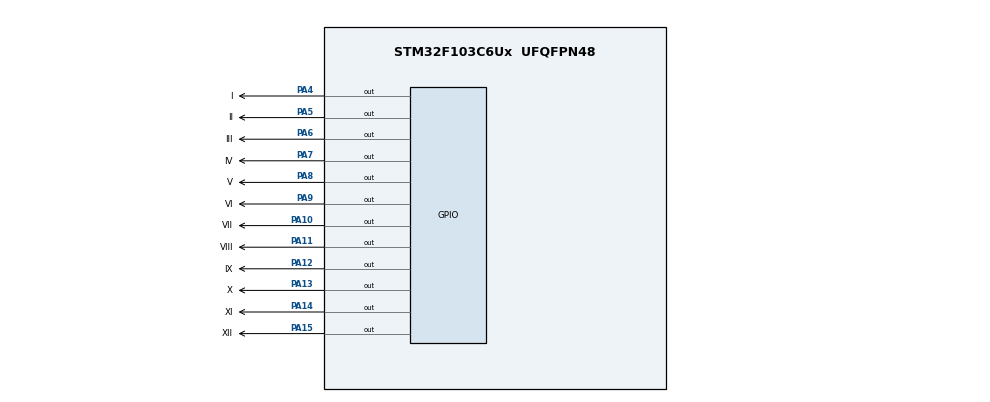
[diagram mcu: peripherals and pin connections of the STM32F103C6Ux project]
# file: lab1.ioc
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Mcu.Family=STM32F1
Mcu.Name=STM32F103C6Ux
Mcu.Package=UFQFPN48
NVIC.PriorityGroup=NVIC_PRIORITYGROUP_4
PA10.GPIO_Label=VII
PA10.Signal=GPIO_Output
PA11.GPIO_Label=VIII
PA11.Signal=GPIO_Output
PA12.GPIO_Label=IX
PA12.Signal=GPIO_Output
PA13.GPIO_Label=X
PA13.Signal=GPIO_Output
PA14.GPIO_Label=XI
PA14.Signal=GPIO_Output
PA15.GPIO_Label=XII
PA15.Signal=GPIO_Output
PA4.GPIO_Label=I
PA4.Signal=GPIO_Output
PA5.GPIO_Label=II
PA5.Signal=GPIO_Output
PA6.GPIO_Label=III
PA6.Signal=GPIO_Output
PA7.GPIO_Label=IV
PA7.Signal=GPIO_Output
PA8.GPIO_Label=V
PA8.Signal=GPIO_Output
PA9.GPIO_Label=VI
PA9.Signal=GPIO_Output
ProjectManager.HeapSize=0x200
ProjectManager.StackSize=0x400
ProjectManager.TargetToolchain=STM32CubeIDE
RCC.APB1Freq_Value=8000000
RCC.APB2Freq_Value=8000000
VP_SYS_VS_ND.Mode=No_Debug
board=custom

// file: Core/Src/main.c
/* USER CODE BEGIN Header */
/**
  ******************************************************************************
  * @file           : main.c
  * @brief          : Main program body
  ******************************************************************************
  * @attention
  *
  * <h2><center>&copy; Copyright (c) 2025 STMicroelectronics.
  * All rights reserved.</center></h2>
  *
  * This software component is licensed by ST under BSD 3-Clause license,
  * the "License"; You may not use this file except in compliance with the
  * License. You may obtain a copy of the License at:
  *                        opensource.org/licenses/BSD-3-Clause
  *
  ******************************************************************************
  */
/* USER CODE END Header */
#include "main.h"

void SystemClock_Config(void);
static void MX_GPIO_Init(void);

void display7SEG1(int num)
{
	if(num==0)
	{
		HAL_GPIO_WritePin(a1_GPIO_Port, a1_Pin, GPIO_PIN_RESET);
		HAL_GPIO_WritePin(b1_GPIO_Port, b1_Pin, GPIO_PIN_RESET);
		HAL_GPIO_WritePin(c1_GPIO_Port, c1_Pin, GPIO_PIN_RESET);
		HAL_GPIO_WritePin(d1_GPIO_Port, d1_Pin, GPIO_PIN_RESET);
		HAL_GPIO_WritePin(e1_GPIO_Port, e1_Pin, GPIO_PIN_RESET);
		HAL_GPIO_WritePin(f1_GPIO_Port, f1_Pin, GPIO_PIN_RESET);
		HAL_GPIO_WritePin(g1_GPIO_Port, g1_Pin, GPIO_PIN_SET);
		return;
	}

	if(num==100)
	{
		HAL_GPIO_WritePin(a1_GPIO_Port, a1_Pin, GPIO_PIN_SET);
		HAL_GPIO_WritePin(b1_GPIO_Port, b1_Pin, GPIO_PIN_RESET);
		HAL_GPIO_WritePin(c1_GPIO_Port, c1_Pin, GPIO_PIN_RESET);
		HAL_GPIO_WritePin(d1_GPIO_Port, d1_Pin, GPIO_PIN_SET);
		HAL_GPIO_WritePin(e1_GPIO_Port, e1_Pin, GPIO_PIN_SET);
		HAL_GPIO_WritePin(f1_GPIO_Port, f1_Pin, GPIO_PIN_SET);
		HAL_GPIO_WritePin(g1_GPIO_Port, g1_Pin, GPIO_PIN_SET);
		return;
	}

	if(num==200)
	{
		HAL_GPIO_WritePin(a1_GPIO_Port, a1_Pin, GPIO_PIN_RESET);
		HAL_GPIO_WritePin(b1_GPIO_Port, b1_Pin, GPIO_PIN_RESET);
		HAL_GPIO_WritePin(c1_GPIO_Port, c1_Pin, GPIO_PIN_SET);
		HAL_GPIO_WritePin(d1_GPIO_Port, d1_Pin, GPIO_PIN_RESET);
		HAL_GPIO_WritePin(e1_GPIO_Port, e1_Pin, GPIO_PIN_RESET);
		HAL_GPIO_WritePin(f1_GPIO_Port, f1_Pin, GPIO_PIN_SET);
		HAL_GPIO_WritePin(g1_GPIO_Port, g1_Pin, GPIO_PIN_RESET);
		return;
	}

	if(num==300)
	{
		HAL_GPIO_WritePin(a1_GPIO_Port, a1_Pin, GPIO_PIN_RESET);
		HAL_GPIO_WritePin(b1_GPIO_Port, b1_Pin, GPIO_PIN_RESET);
		HAL_GPIO_WritePin(c1_GPIO_Port, c1_Pin, GPIO_PIN_RESET);
		HAL_GPIO_WritePin(d1_GPIO_Port, d1_Pin, GPIO_PIN_RESET);
		HAL_GPIO_WritePin(e1_GPIO_Port, e1_Pin, GPIO_PIN_SET);
		HAL_GPIO_WritePin(f1_GPIO_Port, f1_Pin, GPIO_PIN_SET);
		HAL_GPIO_WritePin(g1_GPIO_Port, g1_Pin, GPIO_PIN_RESET);
		return;
	}

	if(num==400)
	{
		HAL_GPIO_WritePin(a1_GPIO_Port, a1_Pin, GPIO_PIN_SET);
		HAL_GPIO_WritePin(b1_GPIO_Port, b1_Pin, GPIO_PIN_RESET);
		HAL_GPIO_WritePin(c1_GPIO_Port, c1_Pin, GPIO_PIN_RESET);
		HAL_GPIO_WritePin(d1_GPIO_Port, d1_Pin, GPIO_PIN_SET);
		HAL_GPIO_WritePin(e1_GPIO_Port, e1_Pin, GPIO_PIN_SET);
		HAL_GPIO_WritePin(f1_GPIO_Port, f1_Pin, GPIO_PIN_RESET);
		HAL_GPIO_WritePin(g1_GPIO_Port, g1_Pin, GPIO_PIN_RESET);
		return;
	}

	if(num==500)
	{
		HAL_GPIO_WritePin(a1_GPIO_Port, a1_Pin, GPIO_PIN_RESET);
		HAL_GPIO_WritePin(b1_GPIO_Port, b1_Pin, GPIO_PIN_SET);
		HAL_GPIO_WritePin(c1_GPIO_Port, c1_Pin, GPIO_PIN_RESET);
		HAL_GPIO_WritePin(d1_GPIO_Port, d1_Pin, GPIO_PIN_RESET);
		HAL_GPIO_WritePin(e1_GPIO_Port, e1_Pin, GPIO_PIN_SET);
		HAL_GPIO_WritePin(f1_GPIO_Port, f1_Pin, GPIO_PIN_RESET);
		HAL_GPIO_WritePin(g1_GPIO_Port, g1_Pin, GPIO_PIN_RESET);
		return;
	}
}

void display7SEG2(int num)
{
	if(num==0)
	{
		HAL_GPIO_WritePin(a2_GPIO_Port, a2_Pin, GPIO_PIN_RESET);
		HAL_GPIO_WritePin(b2_GPIO_Port, b2_Pin, GPIO_PIN_RESET);
		HAL_GPIO_WritePin(c2_GPIO_Port, c2_Pin, GPIO_PIN_RESET);
		HAL_GPIO_WritePin(d2_GPIO_Port, d2_Pin, GPIO_PIN_RESET);
		HAL_GPIO_WritePin(e2_GPIO_Port, e2_Pin, GPIO_PIN_RESET);
		HAL_GPIO_WritePin(f2_GPIO_Port, f2_Pin, GPIO_PIN_RESET);
		HAL_GPIO_WritePin(g2_GPIO_Port, g2_Pin, GPIO_PIN_SET);
		return;
	}

	if(num==100)
	{
		HAL_GPIO_WritePin(a2_GPIO_Port, a2_Pin, GPIO_PIN_SET);
		HAL_GPIO_WritePin(b2_GPIO_Port, b2_Pin, GPIO_PIN_RESET);
		HAL_GPIO_WritePin(c2_GPIO_Port, c2_Pin, GPIO_PIN_RESET);
		HAL_GPIO_WritePin(d2_GPIO_Port, d2_Pin, GPIO_PIN_SET);
		HAL_GPIO_WritePin(e2_GPIO_Port, e2_Pin, GPIO_PIN_SET);
		HAL_GPIO_WritePin(f2_GPIO_Port, f2_Pin, GPIO_PIN_SET);
		HAL_GPIO_WritePin(g2_GPIO_Port, g2_Pin, GPIO_PIN_SET);
		return;
	}

	if(num==200)
	{
		HAL_GPIO_WritePin(a2_GPIO_Port, a2_Pin, GPIO_PIN_RESET);
		HAL_GPIO_WritePin(b2_GPIO_Port, b2_Pin, GPIO_PIN_RESET);
		HAL_GPIO_WritePin(c2_GPIO_Port, c2_Pin, GPIO_PIN_SET);
		HAL_GPIO_WritePin(d2_GPIO_Port, d2_Pin, GPIO_PIN_RESET);
		HAL_GPIO_WritePin(e2_GPIO_Port, e2_Pin, GPIO_PIN_RESET);
		HAL_GPIO_WritePin(f2_GPIO_Port, f2_Pin, GPIO_PIN_SET);
		HAL_GPIO_WritePin(g2_GPIO_Port, g2_Pin, GPIO_PIN_RESET);
		return;
	}

	if(num==300)
	{
		HAL_GPIO_WritePin(a2_GPIO_Port, a2_Pin, GPIO_PIN_RESET);
		HAL_GPIO_WritePin(b2_GPIO_Port, b2_Pin, GPIO_PIN_RESET);
		HAL_GPIO_WritePin(c2_GPIO_Port, c2_Pin, GPIO_PIN_RESET);
		HAL_GPIO_WritePin(d2_GPIO_Port, d2_Pin, GPIO_PIN_RESET);
		HAL_GPIO_WritePin(e2_GPIO_Port, e2_Pin, GPIO_PIN_SET);
		HAL_GPIO_WritePin(f2_GPIO_Port, f2_Pin, GPIO_PIN_SET);
		HAL_GPIO_WritePin(g2_GPIO_Port, g2_Pin, GPIO_PIN_RESET);
		return;
	}

	if(num==400)
	{
		HAL_GPIO_WritePin(a2_GPIO_Port, a2_Pin, GPIO_PIN_SET);
		HAL_GPIO_WritePin(b2_GPIO_Port, b2_Pin, GPIO_PIN_RESET);
		HAL_GPIO_WritePin(c2_GPIO_Port, c2_Pin, GPIO_PIN_RESET);
		HAL_GPIO_WritePin(d2_GPIO_Port, d2_Pin, GPIO_PIN_SET);
		HAL_GPIO_WritePin(e2_GPIO_Port, e2_Pin, GPIO_PIN_SET);
		HAL_GPIO_WritePin(f2_GPIO_Port, f2_Pin, GPIO_PIN_RESET);
		HAL_GPIO_WritePin(g2_GPIO_Port, g2_Pin, GPIO_PIN_RESET);
		return;
	}

	if(num==500)
	{
		HAL_GPIO_WritePin(a2_GPIO_Port, a2_Pin, GPIO_PIN_RESET);
		HAL_GPIO_WritePin(b2_GPIO_Port, b2_Pin, GPIO_PIN_SET);
		HAL_GPIO_WritePin(c2_GPIO_Port, c2_Pin, GPIO_PIN_RESET);
		HAL_GPIO_WritePin(d2_GPIO_Port, d2_Pin, GPIO_PIN_RESET);
		HAL_GPIO_WritePin(e2_GPIO_Port, e2_Pin, GPIO_PIN_SET);
		HAL_GPIO_WritePin(f2_GPIO_Port, f2_Pin, GPIO_PIN_RESET);
		HAL_GPIO_WritePin(g2_GPIO_Port, g2_Pin, GPIO_PIN_RESET);
		return;
	}
}

int main(void)
{

  /* MCU Configuration--------------------------------------------------------*/

  /* Reset of all peripherals, Initializes the Flash interface and the Systick. */
  HAL_Init();

  /* Configure the system clock */
  SystemClock_Config();

  /* Initialize all configured peripherals */
  MX_GPIO_Init();

  /* Infinite loop */
  /* USER CODE BEGIN WHILE */
	int count1=1000;
  int count2=1000;
  int counter1=400;
  int counter2=200;
  HAL_GPIO_WritePin(RED1_GPIO_Port, RED1_Pin, GPIO_PIN_RESET);
  HAL_GPIO_WritePin(YELLOW1_GPIO_Port, YELLOW1_Pin, GPIO_PIN_SET);
  HAL_GPIO_WritePin(GREEN1_GPIO_Port, GREEN1_Pin, GPIO_PIN_SET);
  HAL_GPIO_WritePin(RED2_GPIO_Port, RED2_Pin, GPIO_PIN_SET);
  HAL_GPIO_WritePin(YELLOW2_GPIO_Port, YELLOW2_Pin, GPIO_PIN_SET);
  HAL_GPIO_WritePin(GREEN2_GPIO_Port, GREEN2_Pin, GPIO_PIN_RESET);
  while (1)
  {
    /* USER CODE END WHILE */
	  if(count1==500)
	  {
	      HAL_GPIO_WritePin(RED1_GPIO_Port, RED1_Pin, GPIO_PIN_SET);
	      HAL_GPIO_WritePin(YELLOW1_GPIO_Port, YELLOW1_Pin, GPIO_PIN_SET);
	      HAL_GPIO_WritePin(GREEN1_GPIO_Port, GREEN1_Pin, GPIO_PIN_RESET);
	      counter1=200;

	  }
	  if(count1==200)
	  {
	      HAL_GPIO_WritePin(RED1_GPIO_Port, RED1_Pin, GPIO_PIN_SET);
	      HAL_GPIO_WritePin(YELLOW1_GPIO_Port, YELLOW1_Pin, GPIO_PIN_RESET);
	      HAL_GPIO_WritePin(GREEN1_GPIO_Port, GREEN1_Pin, GPIO_PIN_SET);
	      counter1=100;
	  }
	  if(count1==0)
	  {
	      HAL_GPIO_WritePin(RED1_GPIO_Port, RED1_Pin, GPIO_PIN_RESET);
	      HAL_GPIO_WritePin(YELLOW1_GPIO_Port, YELLOW1_Pin, GPIO_PIN_SET);
	      HAL_GPIO_WritePin(GREEN1_GPIO_Port, GREEN1_Pin, GPIO_PIN_SET);
	      count1=1000;
	    counter1=400;
	  }
	  count1--;
	  display7SEG1(counter1--);

	  if(count2==700)
	  {
	      HAL_GPIO_WritePin(RED2_GPIO_Port, RED2_Pin, GPIO_PIN_SET);
	      HAL_GPIO_WritePin(YELLOW2_GPIO_Port, YELLOW2_Pin, GPIO_PIN_RESET);
	      HAL_GPIO_WritePin(GREEN2_GPIO_Port, GREEN2_Pin, GPIO_PIN_SET);
	    counter2=100;
	  }
	  if(count2==500)
	  {
	      HAL_GPIO_WritePin(RED2_GPIO_Port, RED2_Pin, GPIO_PIN_RESET);
	      HAL_GPIO_WritePin(YELLOW2_GPIO_Port, YELLOW2_Pin, GPIO_PIN_SET);
	      HAL_GPIO_WritePin(GREEN2_GPIO_Port, GREEN2_Pin, GPIO_PIN_SET);
  	    counter2=400;
	  }
	  if(count2==0)
	  {
	      HAL_GPIO_WritePin(RED2_GPIO_Port, RED2_Pin, GPIO_PIN_SET);
	      HAL_GPIO_WritePin(YELLOW2_GPIO_Port, YELLOW2_Pin, GPIO_PIN_SET);
	      HAL_GPIO_WritePin(GREEN2_GPIO_Port, GREEN2_Pin, GPIO_PIN_RESET);
	      count2=1000;
  	    counter2=200;
	  }
	  count2--;
	  display7SEG2(counter2--);
	  HAL_Delay(10);
  }
}

void SystemClock_Config(void)
{
  RCC_OscInitTypeDef RCC_OscInitStruct = {0};
  RCC_ClkInitTypeDef RCC_ClkInitStruct = {0};

  /** Initializes the RCC Oscillators according to the specified parameters
  * in the RCC_OscInitTypeDef structure.
  */
  RCC_OscInitStruct.OscillatorType = RCC_OSCILLATORTYPE_HSI;
  RCC_OscInitStruct.HSIState = RCC_HSI_ON;
  RCC_OscInitStruct.HSICalibrationValue = RCC_HSICALIBRATION_DEFAULT;
  RCC_OscInitStruct.PLL.PLLState = RCC_PLL_NONE;
  if (HAL_RCC_OscConfig(&RCC_OscInitStruct) != HAL_OK)
  {
    Error_Handler();
  }
  /** Initializes the CPU, AHB and APB buses clocks
  */
  RCC_ClkInitStruct.ClockType = RCC_CLOCKTYPE_HCLK|RCC_CLOCKTYPE_SYSCLK
                              |RCC_CLOCKTYPE_PCLK1|RCC_CLOCKTYPE_PCLK2;
  RCC_ClkInitStruct.SYSCLKSource = RCC_SYSCLKSOURCE_HSI;
  RCC_ClkInitStruct.AHBCLKDivider = RCC_SYSCLK_DIV1;
  RCC_ClkInitStruct.APB1CLKDivider = RCC_HCLK_DIV1;
  RCC_ClkInitStruct.APB2CLKDivider = RCC_HCLK_DIV1;

  if (HAL_RCC_ClockConfig(&RCC_ClkInitStruct, FLASH_LATENCY_0) != HAL_OK)
  {
    Error_Handler();
  }
}

static void MX_GPIO_Init(void)
{
  GPIO_InitTypeDef GPIO_InitStruct = {0};

  /* GPIO Ports Clock Enable */
  __HAL_RCC_GPIOA_CLK_ENABLE();
  __HAL_RCC_GPIOB_CLK_ENABLE();

  /*Configure GPIO pin Output Level */
  HAL_GPIO_WritePin(GPIOA, RED2_Pin|YELLOW2_Pin|GREEN2_Pin|RED1_Pin
                          |YELLOW1_Pin|GREEN1_Pin, GPIO_PIN_RESET);

  /*Configure GPIO pin Output Level */
  HAL_GPIO_WritePin(GPIOB, a1_Pin|b1_Pin|c1_Pin|d2_Pin
                          |e2_Pin|f2_Pin|g2_Pin|d1_Pin
                          |e1_Pin|f1_Pin|g1_Pin|a2_Pin
                          |b2_Pin|c2_Pin, GPIO_PIN_RESET);

  /*Configure GPIO pins : RED2_Pin YELLOW2_Pin GREEN2_Pin RED1_Pin
                           YELLOW1_Pin GREEN1_Pin */
  GPIO_InitStruct.Pin = RED2_Pin|YELLOW2_Pin|GREEN2_Pin|RED1_Pin
                          |YELLOW1_Pin|GREEN1_Pin;
  GPIO_InitStruct.Mode = GPIO_MODE_OUTPUT_PP;
  GPIO_InitStruct.Pull = GPIO_NOPULL;
  GPIO_InitStruct.Speed = GPIO_SPEED_FREQ_LOW;
  HAL_GPIO_Init(GPIOA, &GPIO_InitStruct);

  /*Configure GPIO pins : a1_Pin b1_Pin c1_Pin d2_Pin
                           e2_Pin f2_Pin g2_Pin d1_Pin
                           e1_Pin f1_Pin g1_Pin a2_Pin
                           b2_Pin c2_Pin */
  GPIO_InitStruct.Pin = a1_Pin|b1_Pin|c1_Pin|d2_Pin
                          |e2_Pin|f2_Pin|g2_Pin|d1_Pin
                          |e1_Pin|f1_Pin|g1_Pin|a2_Pin
                          |b2_Pin|c2_Pin;
  GPIO_InitStruct.Mode = GPIO_MODE_OUTPUT_PP;
  GPIO_InitStruct.Pull = GPIO_NOPULL;
  GPIO_InitStruct.Speed = GPIO_SPEED_FREQ_LOW;
  HAL_GPIO_Init(GPIOB, &GPIO_InitStruct);

}

void Error_Handler(void)
{
  __disable_irq();
  while (1)
  {
  }
}

/************************ (C) COPYRIGHT STMicroelectronics *****END OF FILE****/
